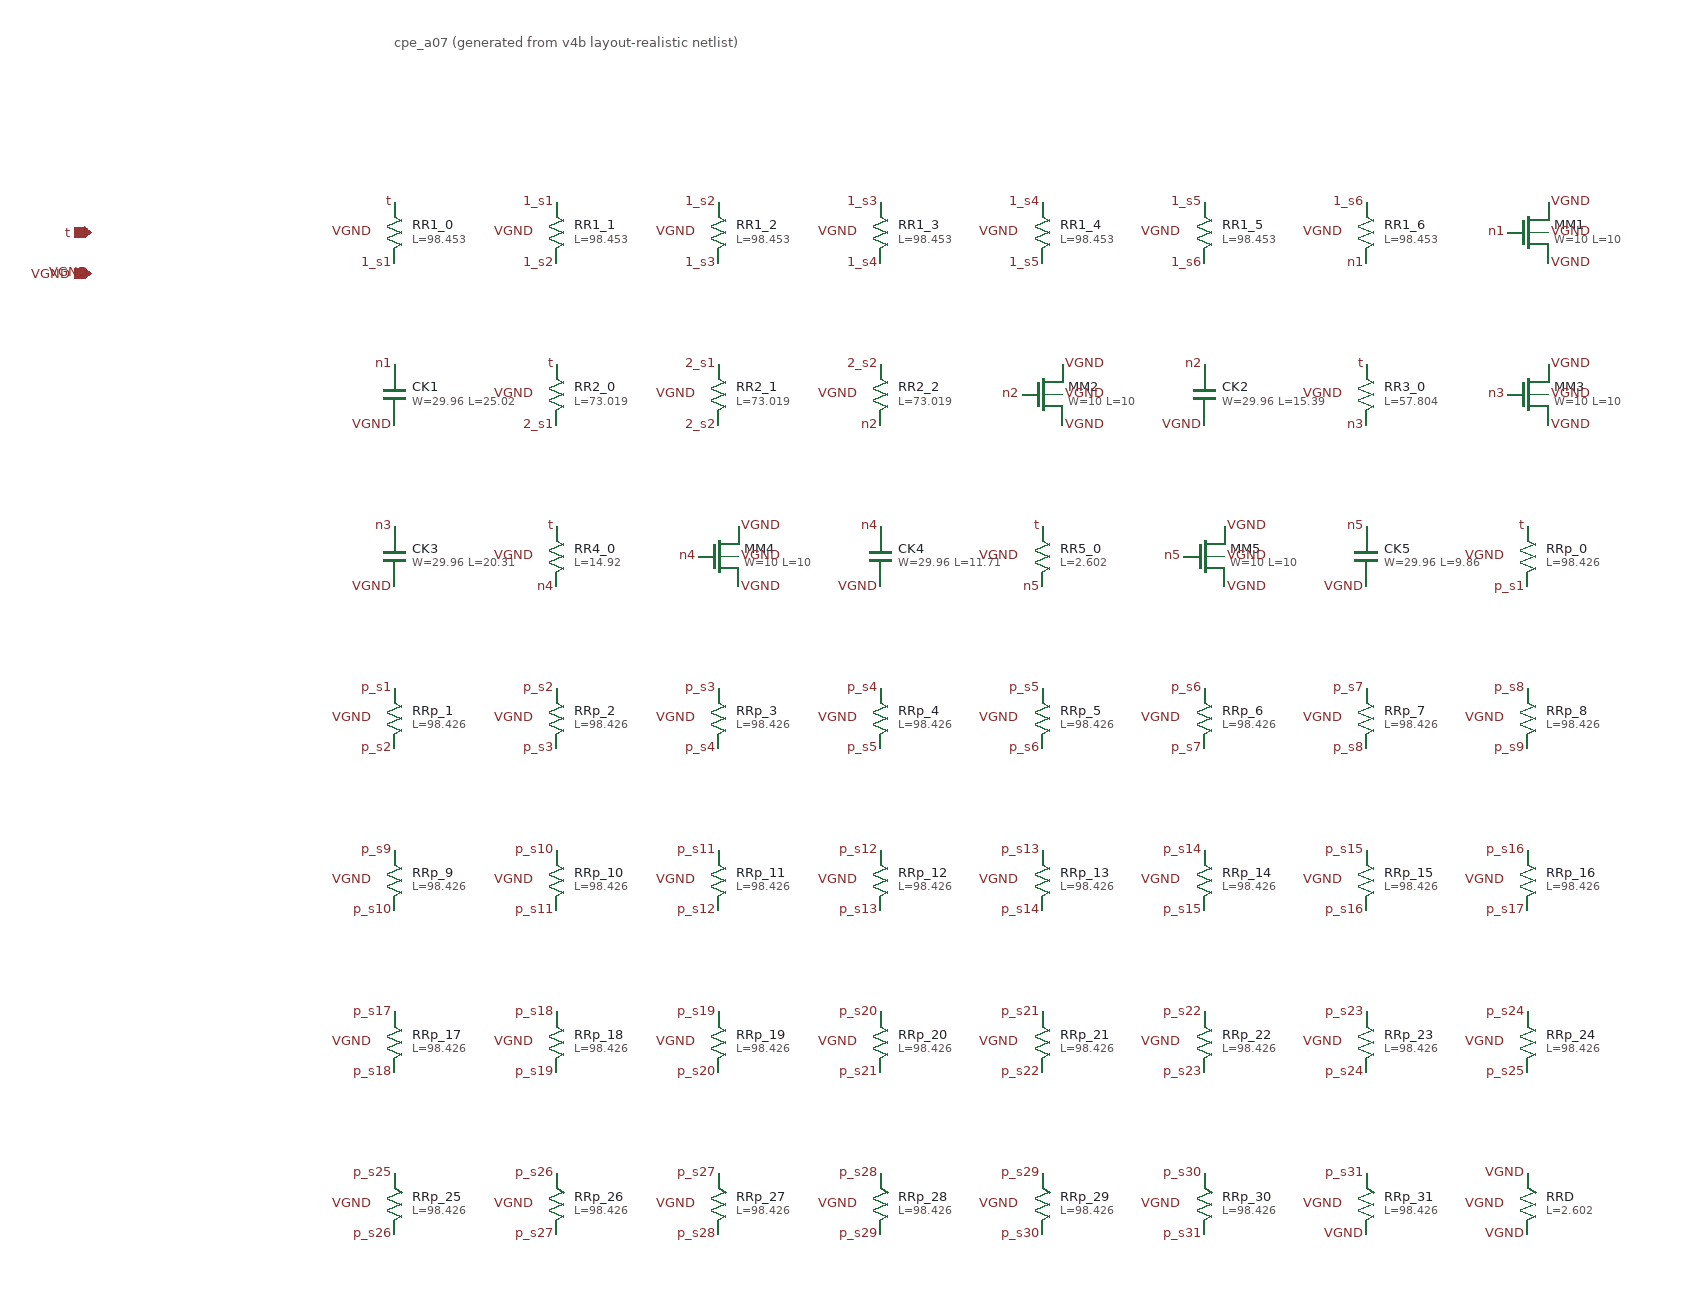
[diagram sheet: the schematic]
v {xschem version=3.4.8RC file_version=1.2}
G {}
K {}
V {}
S {}
E {}
T {cpe_a07  (generated from v4b layout-realistic netlist)} 0 -200 0 0 0.4 0.4 {}
C {iopin.sym} -300 0 0 0 {name=l1 sig_type=std_logic lab=t}
C {iopin.sym} -300 40 0 0 {name=l2 sig_type=std_logic lab=VGND}
C {lab_pin.sym} -300 0 0 0 {name=l3 sig_type=std_logic lab=t}
C {lab_pin.sym} -300 40 0 0 {name=l4 sig_type=std_logic lab=VGND}
C {sky130_fd_pr/res_xhigh_po_0p35.sym} 0 0 0 0 {name=RR1_0 L=98.453 model=res_xhigh_po_0p35 spiceprefix=X mult=1}
C {lab_pin.sym} 0 -30 0 0 {name=l5 sig_type=std_logic lab=t}
C {lab_pin.sym} 0 30 0 0 {name=l6 sig_type=std_logic lab=1_s1}
C {lab_pin.sym} -20 0 0 0 {name=l7 sig_type=std_logic lab=VGND}
C {sky130_fd_pr/res_xhigh_po_0p35.sym} 160 0 0 0 {name=RR1_1 L=98.453 model=res_xhigh_po_0p35 spiceprefix=X mult=1}
C {lab_pin.sym} 160 -30 0 0 {name=l8 sig_type=std_logic lab=1_s1}
C {lab_pin.sym} 160 30 0 0 {name=l9 sig_type=std_logic lab=1_s2}
C {lab_pin.sym} 140 0 0 0 {name=l10 sig_type=std_logic lab=VGND}
C {sky130_fd_pr/res_xhigh_po_0p35.sym} 320 0 0 0 {name=RR1_2 L=98.453 model=res_xhigh_po_0p35 spiceprefix=X mult=1}
C {lab_pin.sym} 320 -30 0 0 {name=l11 sig_type=std_logic lab=1_s2}
C {lab_pin.sym} 320 30 0 0 {name=l12 sig_type=std_logic lab=1_s3}
C {lab_pin.sym} 300 0 0 0 {name=l13 sig_type=std_logic lab=VGND}
C {sky130_fd_pr/res_xhigh_po_0p35.sym} 480 0 0 0 {name=RR1_3 L=98.453 model=res_xhigh_po_0p35 spiceprefix=X mult=1}
C {lab_pin.sym} 480 -30 0 0 {name=l14 sig_type=std_logic lab=1_s3}
C {lab_pin.sym} 480 30 0 0 {name=l15 sig_type=std_logic lab=1_s4}
C {lab_pin.sym} 460 0 0 0 {name=l16 sig_type=std_logic lab=VGND}
C {sky130_fd_pr/res_xhigh_po_0p35.sym} 640 0 0 0 {name=RR1_4 L=98.453 model=res_xhigh_po_0p35 spiceprefix=X mult=1}
C {lab_pin.sym} 640 -30 0 0 {name=l17 sig_type=std_logic lab=1_s4}
C {lab_pin.sym} 640 30 0 0 {name=l18 sig_type=std_logic lab=1_s5}
C {lab_pin.sym} 620 0 0 0 {name=l19 sig_type=std_logic lab=VGND}
C {sky130_fd_pr/res_xhigh_po_0p35.sym} 800 0 0 0 {name=RR1_5 L=98.453 model=res_xhigh_po_0p35 spiceprefix=X mult=1}
C {lab_pin.sym} 800 -30 0 0 {name=l20 sig_type=std_logic lab=1_s5}
C {lab_pin.sym} 800 30 0 0 {name=l21 sig_type=std_logic lab=1_s6}
C {lab_pin.sym} 780 0 0 0 {name=l22 sig_type=std_logic lab=VGND}
C {sky130_fd_pr/res_xhigh_po_0p35.sym} 960 0 0 0 {name=RR1_6 L=98.453 model=res_xhigh_po_0p35 spiceprefix=X mult=1}
C {lab_pin.sym} 960 -30 0 0 {name=l23 sig_type=std_logic lab=1_s6}
C {lab_pin.sym} 960 30 0 0 {name=l24 sig_type=std_logic lab=n1}
C {lab_pin.sym} 940 0 0 0 {name=l25 sig_type=std_logic lab=VGND}
C {sky130_fd_pr/nfet_01v8.sym} 1120 0 0 0 {name=MM1 W=10 L=10 nf=1 mult=108 model=nfet_01v8 spiceprefix=X}
C {lab_pin.sym} 1140 -30 0 1 {name=l26 sig_type=std_logic lab=VGND}
C {lab_pin.sym} 1100 0 0 0 {name=l27 sig_type=std_logic lab=n1}
C {lab_pin.sym} 1140 30 0 1 {name=l28 sig_type=std_logic lab=VGND}
C {lab_pin.sym} 1140 0 0 1 {name=l29 sig_type=std_logic lab=VGND}
C {sky130_fd_pr/cap_mim_m3_1.sym} 0 160 0 0 {name=CK1 model=cap_mim_m3_1 W=29.96 L=25.02 MF=12 spiceprefix=X}
C {lab_pin.sym} 0 130 0 0 {name=l30 sig_type=std_logic lab=n1}
C {lab_pin.sym} 0 190 0 0 {name=l31 sig_type=std_logic lab=VGND}
C {sky130_fd_pr/res_xhigh_po_0p35.sym} 160 160 0 0 {name=RR2_0 L=73.019 model=res_xhigh_po_0p35 spiceprefix=X mult=1}
C {lab_pin.sym} 160 130 0 0 {name=l32 sig_type=std_logic lab=t}
C {lab_pin.sym} 160 190 0 0 {name=l33 sig_type=std_logic lab=2_s1}
C {lab_pin.sym} 140 160 0 0 {name=l34 sig_type=std_logic lab=VGND}
C {sky130_fd_pr/res_xhigh_po_0p35.sym} 320 160 0 0 {name=RR2_1 L=73.019 model=res_xhigh_po_0p35 spiceprefix=X mult=1}
C {lab_pin.sym} 320 130 0 0 {name=l35 sig_type=std_logic lab=2_s1}
C {lab_pin.sym} 320 190 0 0 {name=l36 sig_type=std_logic lab=2_s2}
C {lab_pin.sym} 300 160 0 0 {name=l37 sig_type=std_logic lab=VGND}
C {sky130_fd_pr/res_xhigh_po_0p35.sym} 480 160 0 0 {name=RR2_2 L=73.019 model=res_xhigh_po_0p35 spiceprefix=X mult=1}
C {lab_pin.sym} 480 130 0 0 {name=l38 sig_type=std_logic lab=2_s2}
C {lab_pin.sym} 480 190 0 0 {name=l39 sig_type=std_logic lab=n2}
C {lab_pin.sym} 460 160 0 0 {name=l40 sig_type=std_logic lab=VGND}
C {sky130_fd_pr/nfet_01v8.sym} 640 160 0 0 {name=MM2 W=10 L=10 nf=1 mult=46 model=nfet_01v8 spiceprefix=X}
C {lab_pin.sym} 660 130 0 1 {name=l41 sig_type=std_logic lab=VGND}
C {lab_pin.sym} 620 160 0 0 {name=l42 sig_type=std_logic lab=n2}
C {lab_pin.sym} 660 190 0 1 {name=l43 sig_type=std_logic lab=VGND}
C {lab_pin.sym} 660 160 0 1 {name=l44 sig_type=std_logic lab=VGND}
C {sky130_fd_pr/cap_mim_m3_1.sym} 800 160 0 0 {name=CK2 model=cap_mim_m3_1 W=29.96 L=15.39 MF=8 spiceprefix=X}
C {lab_pin.sym} 800 130 0 0 {name=l45 sig_type=std_logic lab=n2}
C {lab_pin.sym} 800 190 0 0 {name=l46 sig_type=std_logic lab=VGND}
C {sky130_fd_pr/res_xhigh_po_0p35.sym} 960 160 0 0 {name=RR3_0 L=57.804 model=res_xhigh_po_0p35 spiceprefix=X mult=1}
C {lab_pin.sym} 960 130 0 0 {name=l47 sig_type=std_logic lab=t}
C {lab_pin.sym} 960 190 0 0 {name=l48 sig_type=std_logic lab=n3}
C {lab_pin.sym} 940 160 0 0 {name=l49 sig_type=std_logic lab=VGND}
C {sky130_fd_pr/nfet_01v8.sym} 1120 160 0 0 {name=MM3 W=10 L=10 nf=1 mult=29 model=nfet_01v8 spiceprefix=X}
C {lab_pin.sym} 1140 130 0 1 {name=l50 sig_type=std_logic lab=VGND}
C {lab_pin.sym} 1100 160 0 0 {name=l51 sig_type=std_logic lab=n3}
C {lab_pin.sym} 1140 190 0 1 {name=l52 sig_type=std_logic lab=VGND}
C {lab_pin.sym} 1140 160 0 1 {name=l53 sig_type=std_logic lab=VGND}
C {sky130_fd_pr/cap_mim_m3_1.sym} 0 320 0 0 {name=CK3 model=cap_mim_m3_1 W=29.96 L=20.31 MF=4 spiceprefix=X}
C {lab_pin.sym} 0 290 0 0 {name=l54 sig_type=std_logic lab=n3}
C {lab_pin.sym} 0 350 0 0 {name=l55 sig_type=std_logic lab=VGND}
C {sky130_fd_pr/res_xhigh_po_0p35.sym} 160 320 0 0 {name=RR4_0 L=14.92 model=res_xhigh_po_0p35 spiceprefix=X mult=1}
C {lab_pin.sym} 160 290 0 0 {name=l56 sig_type=std_logic lab=t}
C {lab_pin.sym} 160 350 0 0 {name=l57 sig_type=std_logic lab=n4}
C {lab_pin.sym} 140 320 0 0 {name=l58 sig_type=std_logic lab=VGND}
C {sky130_fd_pr/nfet_01v8.sym} 320 320 0 0 {name=MM4 W=10 L=10 nf=1 mult=18 model=nfet_01v8 spiceprefix=X}
C {lab_pin.sym} 340 290 0 1 {name=l59 sig_type=std_logic lab=VGND}
C {lab_pin.sym} 300 320 0 0 {name=l60 sig_type=std_logic lab=n4}
C {lab_pin.sym} 340 350 0 1 {name=l61 sig_type=std_logic lab=VGND}
C {lab_pin.sym} 340 320 0 1 {name=l62 sig_type=std_logic lab=VGND}
C {sky130_fd_pr/cap_mim_m3_1.sym} 480 320 0 0 {name=CK4 model=cap_mim_m3_1 W=29.96 L=11.71 MF=4 spiceprefix=X}
C {lab_pin.sym} 480 290 0 0 {name=l63 sig_type=std_logic lab=n4}
C {lab_pin.sym} 480 350 0 0 {name=l64 sig_type=std_logic lab=VGND}
C {sky130_fd_pr/res_xhigh_po_0p35.sym} 640 320 0 0 {name=RR5_0 L=2.602 model=res_xhigh_po_0p35 spiceprefix=X mult=1}
C {lab_pin.sym} 640 290 0 0 {name=l65 sig_type=std_logic lab=t}
C {lab_pin.sym} 640 350 0 0 {name=l66 sig_type=std_logic lab=n5}
C {lab_pin.sym} 620 320 0 0 {name=l67 sig_type=std_logic lab=VGND}
C {sky130_fd_pr/nfet_01v8.sym} 800 320 0 0 {name=MM5 W=10 L=10 nf=1 mult=13 model=nfet_01v8 spiceprefix=X}
C {lab_pin.sym} 820 290 0 1 {name=l68 sig_type=std_logic lab=VGND}
C {lab_pin.sym} 780 320 0 0 {name=l69 sig_type=std_logic lab=n5}
C {lab_pin.sym} 820 350 0 1 {name=l70 sig_type=std_logic lab=VGND}
C {lab_pin.sym} 820 320 0 1 {name=l71 sig_type=std_logic lab=VGND}
C {sky130_fd_pr/cap_mim_m3_1.sym} 960 320 0 0 {name=CK5 model=cap_mim_m3_1 W=29.96 L=9.86 MF=4 spiceprefix=X}
C {lab_pin.sym} 960 290 0 0 {name=l72 sig_type=std_logic lab=n5}
C {lab_pin.sym} 960 350 0 0 {name=l73 sig_type=std_logic lab=VGND}
C {sky130_fd_pr/res_xhigh_po_0p35.sym} 1120 320 0 0 {name=RRp_0 L=98.426 model=res_xhigh_po_0p35 spiceprefix=X mult=1}
C {lab_pin.sym} 1120 290 0 0 {name=l74 sig_type=std_logic lab=t}
C {lab_pin.sym} 1120 350 0 0 {name=l75 sig_type=std_logic lab=p_s1}
C {lab_pin.sym} 1100 320 0 0 {name=l76 sig_type=std_logic lab=VGND}
C {sky130_fd_pr/res_xhigh_po_0p35.sym} 0 480 0 0 {name=RRp_1 L=98.426 model=res_xhigh_po_0p35 spiceprefix=X mult=1}
C {lab_pin.sym} 0 450 0 0 {name=l77 sig_type=std_logic lab=p_s1}
C {lab_pin.sym} 0 510 0 0 {name=l78 sig_type=std_logic lab=p_s2}
C {lab_pin.sym} -20 480 0 0 {name=l79 sig_type=std_logic lab=VGND}
C {sky130_fd_pr/res_xhigh_po_0p35.sym} 160 480 0 0 {name=RRp_2 L=98.426 model=res_xhigh_po_0p35 spiceprefix=X mult=1}
C {lab_pin.sym} 160 450 0 0 {name=l80 sig_type=std_logic lab=p_s2}
C {lab_pin.sym} 160 510 0 0 {name=l81 sig_type=std_logic lab=p_s3}
C {lab_pin.sym} 140 480 0 0 {name=l82 sig_type=std_logic lab=VGND}
C {sky130_fd_pr/res_xhigh_po_0p35.sym} 320 480 0 0 {name=RRp_3 L=98.426 model=res_xhigh_po_0p35 spiceprefix=X mult=1}
C {lab_pin.sym} 320 450 0 0 {name=l83 sig_type=std_logic lab=p_s3}
C {lab_pin.sym} 320 510 0 0 {name=l84 sig_type=std_logic lab=p_s4}
C {lab_pin.sym} 300 480 0 0 {name=l85 sig_type=std_logic lab=VGND}
C {sky130_fd_pr/res_xhigh_po_0p35.sym} 480 480 0 0 {name=RRp_4 L=98.426 model=res_xhigh_po_0p35 spiceprefix=X mult=1}
C {lab_pin.sym} 480 450 0 0 {name=l86 sig_type=std_logic lab=p_s4}
C {lab_pin.sym} 480 510 0 0 {name=l87 sig_type=std_logic lab=p_s5}
C {lab_pin.sym} 460 480 0 0 {name=l88 sig_type=std_logic lab=VGND}
C {sky130_fd_pr/res_xhigh_po_0p35.sym} 640 480 0 0 {name=RRp_5 L=98.426 model=res_xhigh_po_0p35 spiceprefix=X mult=1}
C {lab_pin.sym} 640 450 0 0 {name=l89 sig_type=std_logic lab=p_s5}
C {lab_pin.sym} 640 510 0 0 {name=l90 sig_type=std_logic lab=p_s6}
C {lab_pin.sym} 620 480 0 0 {name=l91 sig_type=std_logic lab=VGND}
C {sky130_fd_pr/res_xhigh_po_0p35.sym} 800 480 0 0 {name=RRp_6 L=98.426 model=res_xhigh_po_0p35 spiceprefix=X mult=1}
C {lab_pin.sym} 800 450 0 0 {name=l92 sig_type=std_logic lab=p_s6}
C {lab_pin.sym} 800 510 0 0 {name=l93 sig_type=std_logic lab=p_s7}
C {lab_pin.sym} 780 480 0 0 {name=l94 sig_type=std_logic lab=VGND}
C {sky130_fd_pr/res_xhigh_po_0p35.sym} 960 480 0 0 {name=RRp_7 L=98.426 model=res_xhigh_po_0p35 spiceprefix=X mult=1}
C {lab_pin.sym} 960 450 0 0 {name=l95 sig_type=std_logic lab=p_s7}
C {lab_pin.sym} 960 510 0 0 {name=l96 sig_type=std_logic lab=p_s8}
C {lab_pin.sym} 940 480 0 0 {name=l97 sig_type=std_logic lab=VGND}
C {sky130_fd_pr/res_xhigh_po_0p35.sym} 1120 480 0 0 {name=RRp_8 L=98.426 model=res_xhigh_po_0p35 spiceprefix=X mult=1}
C {lab_pin.sym} 1120 450 0 0 {name=l98 sig_type=std_logic lab=p_s8}
C {lab_pin.sym} 1120 510 0 0 {name=l99 sig_type=std_logic lab=p_s9}
C {lab_pin.sym} 1100 480 0 0 {name=l100 sig_type=std_logic lab=VGND}
C {sky130_fd_pr/res_xhigh_po_0p35.sym} 0 640 0 0 {name=RRp_9 L=98.426 model=res_xhigh_po_0p35 spiceprefix=X mult=1}
C {lab_pin.sym} 0 610 0 0 {name=l101 sig_type=std_logic lab=p_s9}
C {lab_pin.sym} 0 670 0 0 {name=l102 sig_type=std_logic lab=p_s10}
C {lab_pin.sym} -20 640 0 0 {name=l103 sig_type=std_logic lab=VGND}
C {sky130_fd_pr/res_xhigh_po_0p35.sym} 160 640 0 0 {name=RRp_10 L=98.426 model=res_xhigh_po_0p35 spiceprefix=X mult=1}
C {lab_pin.sym} 160 610 0 0 {name=l104 sig_type=std_logic lab=p_s10}
C {lab_pin.sym} 160 670 0 0 {name=l105 sig_type=std_logic lab=p_s11}
C {lab_pin.sym} 140 640 0 0 {name=l106 sig_type=std_logic lab=VGND}
C {sky130_fd_pr/res_xhigh_po_0p35.sym} 320 640 0 0 {name=RRp_11 L=98.426 model=res_xhigh_po_0p35 spiceprefix=X mult=1}
C {lab_pin.sym} 320 610 0 0 {name=l107 sig_type=std_logic lab=p_s11}
C {lab_pin.sym} 320 670 0 0 {name=l108 sig_type=std_logic lab=p_s12}
C {lab_pin.sym} 300 640 0 0 {name=l109 sig_type=std_logic lab=VGND}
C {sky130_fd_pr/res_xhigh_po_0p35.sym} 480 640 0 0 {name=RRp_12 L=98.426 model=res_xhigh_po_0p35 spiceprefix=X mult=1}
C {lab_pin.sym} 480 610 0 0 {name=l110 sig_type=std_logic lab=p_s12}
C {lab_pin.sym} 480 670 0 0 {name=l111 sig_type=std_logic lab=p_s13}
C {lab_pin.sym} 460 640 0 0 {name=l112 sig_type=std_logic lab=VGND}
C {sky130_fd_pr/res_xhigh_po_0p35.sym} 640 640 0 0 {name=RRp_13 L=98.426 model=res_xhigh_po_0p35 spiceprefix=X mult=1}
C {lab_pin.sym} 640 610 0 0 {name=l113 sig_type=std_logic lab=p_s13}
C {lab_pin.sym} 640 670 0 0 {name=l114 sig_type=std_logic lab=p_s14}
C {lab_pin.sym} 620 640 0 0 {name=l115 sig_type=std_logic lab=VGND}
C {sky130_fd_pr/res_xhigh_po_0p35.sym} 800 640 0 0 {name=RRp_14 L=98.426 model=res_xhigh_po_0p35 spiceprefix=X mult=1}
C {lab_pin.sym} 800 610 0 0 {name=l116 sig_type=std_logic lab=p_s14}
C {lab_pin.sym} 800 670 0 0 {name=l117 sig_type=std_logic lab=p_s15}
C {lab_pin.sym} 780 640 0 0 {name=l118 sig_type=std_logic lab=VGND}
C {sky130_fd_pr/res_xhigh_po_0p35.sym} 960 640 0 0 {name=RRp_15 L=98.426 model=res_xhigh_po_0p35 spiceprefix=X mult=1}
C {lab_pin.sym} 960 610 0 0 {name=l119 sig_type=std_logic lab=p_s15}
C {lab_pin.sym} 960 670 0 0 {name=l120 sig_type=std_logic lab=p_s16}
C {lab_pin.sym} 940 640 0 0 {name=l121 sig_type=std_logic lab=VGND}
C {sky130_fd_pr/res_xhigh_po_0p35.sym} 1120 640 0 0 {name=RRp_16 L=98.426 model=res_xhigh_po_0p35 spiceprefix=X mult=1}
C {lab_pin.sym} 1120 610 0 0 {name=l122 sig_type=std_logic lab=p_s16}
C {lab_pin.sym} 1120 670 0 0 {name=l123 sig_type=std_logic lab=p_s17}
C {lab_pin.sym} 1100 640 0 0 {name=l124 sig_type=std_logic lab=VGND}
C {sky130_fd_pr/res_xhigh_po_0p35.sym} 0 800 0 0 {name=RRp_17 L=98.426 model=res_xhigh_po_0p35 spiceprefix=X mult=1}
C {lab_pin.sym} 0 770 0 0 {name=l125 sig_type=std_logic lab=p_s17}
C {lab_pin.sym} 0 830 0 0 {name=l126 sig_type=std_logic lab=p_s18}
C {lab_pin.sym} -20 800 0 0 {name=l127 sig_type=std_logic lab=VGND}
C {sky130_fd_pr/res_xhigh_po_0p35.sym} 160 800 0 0 {name=RRp_18 L=98.426 model=res_xhigh_po_0p35 spiceprefix=X mult=1}
C {lab_pin.sym} 160 770 0 0 {name=l128 sig_type=std_logic lab=p_s18}
C {lab_pin.sym} 160 830 0 0 {name=l129 sig_type=std_logic lab=p_s19}
C {lab_pin.sym} 140 800 0 0 {name=l130 sig_type=std_logic lab=VGND}
C {sky130_fd_pr/res_xhigh_po_0p35.sym} 320 800 0 0 {name=RRp_19 L=98.426 model=res_xhigh_po_0p35 spiceprefix=X mult=1}
C {lab_pin.sym} 320 770 0 0 {name=l131 sig_type=std_logic lab=p_s19}
C {lab_pin.sym} 320 830 0 0 {name=l132 sig_type=std_logic lab=p_s20}
C {lab_pin.sym} 300 800 0 0 {name=l133 sig_type=std_logic lab=VGND}
C {sky130_fd_pr/res_xhigh_po_0p35.sym} 480 800 0 0 {name=RRp_20 L=98.426 model=res_xhigh_po_0p35 spiceprefix=X mult=1}
C {lab_pin.sym} 480 770 0 0 {name=l134 sig_type=std_logic lab=p_s20}
C {lab_pin.sym} 480 830 0 0 {name=l135 sig_type=std_logic lab=p_s21}
C {lab_pin.sym} 460 800 0 0 {name=l136 sig_type=std_logic lab=VGND}
C {sky130_fd_pr/res_xhigh_po_0p35.sym} 640 800 0 0 {name=RRp_21 L=98.426 model=res_xhigh_po_0p35 spiceprefix=X mult=1}
C {lab_pin.sym} 640 770 0 0 {name=l137 sig_type=std_logic lab=p_s21}
C {lab_pin.sym} 640 830 0 0 {name=l138 sig_type=std_logic lab=p_s22}
C {lab_pin.sym} 620 800 0 0 {name=l139 sig_type=std_logic lab=VGND}
C {sky130_fd_pr/res_xhigh_po_0p35.sym} 800 800 0 0 {name=RRp_22 L=98.426 model=res_xhigh_po_0p35 spiceprefix=X mult=1}
C {lab_pin.sym} 800 770 0 0 {name=l140 sig_type=std_logic lab=p_s22}
C {lab_pin.sym} 800 830 0 0 {name=l141 sig_type=std_logic lab=p_s23}
C {lab_pin.sym} 780 800 0 0 {name=l142 sig_type=std_logic lab=VGND}
C {sky130_fd_pr/res_xhigh_po_0p35.sym} 960 800 0 0 {name=RRp_23 L=98.426 model=res_xhigh_po_0p35 spiceprefix=X mult=1}
C {lab_pin.sym} 960 770 0 0 {name=l143 sig_type=std_logic lab=p_s23}
C {lab_pin.sym} 960 830 0 0 {name=l144 sig_type=std_logic lab=p_s24}
C {lab_pin.sym} 940 800 0 0 {name=l145 sig_type=std_logic lab=VGND}
C {sky130_fd_pr/res_xhigh_po_0p35.sym} 1120 800 0 0 {name=RRp_24 L=98.426 model=res_xhigh_po_0p35 spiceprefix=X mult=1}
C {lab_pin.sym} 1120 770 0 0 {name=l146 sig_type=std_logic lab=p_s24}
C {lab_pin.sym} 1120 830 0 0 {name=l147 sig_type=std_logic lab=p_s25}
C {lab_pin.sym} 1100 800 0 0 {name=l148 sig_type=std_logic lab=VGND}
C {sky130_fd_pr/res_xhigh_po_0p35.sym} 0 960 0 0 {name=RRp_25 L=98.426 model=res_xhigh_po_0p35 spiceprefix=X mult=1}
C {lab_pin.sym} 0 930 0 0 {name=l149 sig_type=std_logic lab=p_s25}
C {lab_pin.sym} 0 990 0 0 {name=l150 sig_type=std_logic lab=p_s26}
C {lab_pin.sym} -20 960 0 0 {name=l151 sig_type=std_logic lab=VGND}
C {sky130_fd_pr/res_xhigh_po_0p35.sym} 160 960 0 0 {name=RRp_26 L=98.426 model=res_xhigh_po_0p35 spiceprefix=X mult=1}
C {lab_pin.sym} 160 930 0 0 {name=l152 sig_type=std_logic lab=p_s26}
C {lab_pin.sym} 160 990 0 0 {name=l153 sig_type=std_logic lab=p_s27}
C {lab_pin.sym} 140 960 0 0 {name=l154 sig_type=std_logic lab=VGND}
C {sky130_fd_pr/res_xhigh_po_0p35.sym} 320 960 0 0 {name=RRp_27 L=98.426 model=res_xhigh_po_0p35 spiceprefix=X mult=1}
C {lab_pin.sym} 320 930 0 0 {name=l155 sig_type=std_logic lab=p_s27}
C {lab_pin.sym} 320 990 0 0 {name=l156 sig_type=std_logic lab=p_s28}
C {lab_pin.sym} 300 960 0 0 {name=l157 sig_type=std_logic lab=VGND}
C {sky130_fd_pr/res_xhigh_po_0p35.sym} 480 960 0 0 {name=RRp_28 L=98.426 model=res_xhigh_po_0p35 spiceprefix=X mult=1}
C {lab_pin.sym} 480 930 0 0 {name=l158 sig_type=std_logic lab=p_s28}
C {lab_pin.sym} 480 990 0 0 {name=l159 sig_type=std_logic lab=p_s29}
C {lab_pin.sym} 460 960 0 0 {name=l160 sig_type=std_logic lab=VGND}
C {sky130_fd_pr/res_xhigh_po_0p35.sym} 640 960 0 0 {name=RRp_29 L=98.426 model=res_xhigh_po_0p35 spiceprefix=X mult=1}
C {lab_pin.sym} 640 930 0 0 {name=l161 sig_type=std_logic lab=p_s29}
C {lab_pin.sym} 640 990 0 0 {name=l162 sig_type=std_logic lab=p_s30}
C {lab_pin.sym} 620 960 0 0 {name=l163 sig_type=std_logic lab=VGND}
C {sky130_fd_pr/res_xhigh_po_0p35.sym} 800 960 0 0 {name=RRp_30 L=98.426 model=res_xhigh_po_0p35 spiceprefix=X mult=1}
C {lab_pin.sym} 800 930 0 0 {name=l164 sig_type=std_logic lab=p_s30}
C {lab_pin.sym} 800 990 0 0 {name=l165 sig_type=std_logic lab=p_s31}
C {lab_pin.sym} 780 960 0 0 {name=l166 sig_type=std_logic lab=VGND}
C {sky130_fd_pr/res_xhigh_po_0p35.sym} 960 960 0 0 {name=RRp_31 L=98.426 model=res_xhigh_po_0p35 spiceprefix=X mult=1}
C {lab_pin.sym} 960 930 0 0 {name=l167 sig_type=std_logic lab=p_s31}
C {lab_pin.sym} 960 990 0 0 {name=l168 sig_type=std_logic lab=VGND}
C {lab_pin.sym} 940 960 0 0 {name=l169 sig_type=std_logic lab=VGND}
C {sky130_fd_pr/res_xhigh_po_0p35.sym} 1120 960 0 0 {name=RRD L=2.602 model=res_xhigh_po_0p35 spiceprefix=X mult=1}
C {lab_pin.sym} 1120 930 0 0 {name=l170 sig_type=std_logic lab=VGND}
C {lab_pin.sym} 1120 990 0 0 {name=l171 sig_type=std_logic lab=VGND}
C {lab_pin.sym} 1100 960 0 0 {name=l172 sig_type=std_logic lab=VGND}
